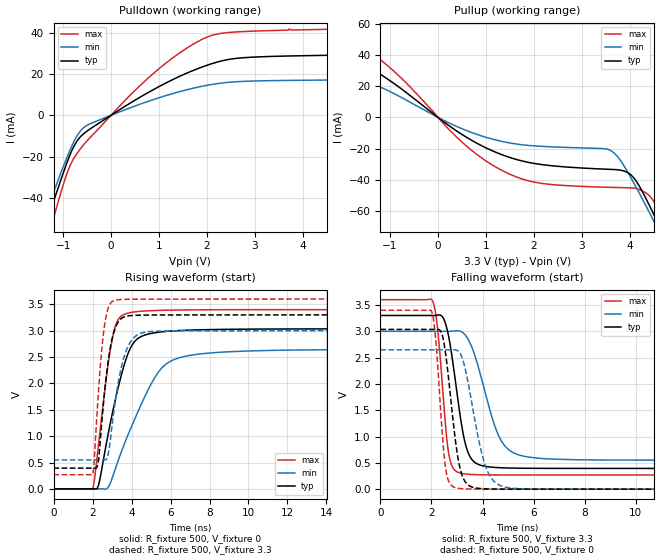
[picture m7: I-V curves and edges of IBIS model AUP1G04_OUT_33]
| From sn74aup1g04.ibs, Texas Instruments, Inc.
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[Model]   AUP1G04_OUT_33
Model_type  Output
Vref =   0
Rref =   1E6
Cref =   30p
Vmeas =   1.65
| variable   typ   min   max
C_comp   2.81pF   1.90pF   4.21pF
| C_pullup   3.21pF   1.90pF   4.21pF
| C_pulldown   2.42pF   2.21pF   2.99pF
[Temperature Range]   40   100   -40
| Ambient temperature   25   85   -40
[Voltage range]   3.3   3   3.6
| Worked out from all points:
|   slope of the pulldown table from 0 to 0.495 V, typ, clamps not added: 68.4 ohm
|   slope of the pullup table from 0 to 0.495 V, typ, clamps not added: 45.8 ohm
|   rising waveform, R_fixture 500, V_fixture 0: 20-80 % time 1.1ns typ, 1.9ns min, 694ps max; typ from 0 V to 3.04 V
|   falling waveform, R_fixture 500, V_fixture 3.3: 20-80 % time 533ps typ, 890ps min, 340ps max; typ from 3.3 V to 0.394 V
|   rising waveform, R_fixture 500, V_fixture 3.3: 20-80 % time 521ps typ, 675ps min, 407ps max; typ from 0.394 V to 3.3 V
|   falling waveform, R_fixture 500, V_fixture 0: 20-80 % time 440ps typ, 658ps min, 299ps max; typ from 3.04 V to 0 V
[Pulldown]
| AUP1G04_OUT_33
|   Voltage   I(typ)   I(min)   I(max)
-3.6V     -218.7mA   -196.3mA   -248.6mA
-1.515V   -64.37mA   -57.31mA   -75.82mA
-1.39V    -55.35mA   -49.29mA   -65.41mA
-1.275V   -47.14mA   -42mA      -55.89mA
-870mV    -19.93mA   -17.62mA   -25.18mA
-720mV    -12.85mA   -10.38mA   -18.82mA
-545mV    -8.444mA   -5.509mA   -13.51mA
940mV     13.13mA    8.018mA    21.36mA
1.5V      19.56mA    11.86mA    31.27mA
2.045V    24.53mA    14.67mA    38.2mA
3.1V      28.27mA    16.63mA    40.81mA
7.2V      29.73mA    17.36mA    42.67mA
[Pullup]
| AUP1G04_OUT_33
|   Voltage   I(typ)   I(min)   I(max)
-3.6V     42.88mA    27.27mA    57.92mA
-2.465V   31.53mA    19.52mA    45.85mA
-1.53V    32.87mA    22.09mA    44.95mA
-755mV    18.1mA     12.64mA    24.89mA
555mV     -11.98mA   -7.942mA   -17.3mA
1.65V     -27.07mA   -17.13mA   -38.31mA
3.61V     -33.32mA   -21.39mA   -44.82mA
4.08V     -38.63mA   -41.77mA   -45.28mA
4.375V    -54.25mA   -58.9mA    -49.24mA
4.565V    -66.24mA   -70.37mA   -57.33mA
4.775V    -80.02mA   -83.29mA   -71.37mA
7.2V      -250.7mA   -240.9mA   -257mA
[Ramp]
| AUP1G04_OUT_33
| variable   typ   min   max
dV/dt_r   1.82/1.11E-09   1.59/1.90E-09   2.04/6.96E-10
dV/dt_f   1.75/5.39E-10   1.48/8.97E-10   2.01/3.44E-10
R_load = 500
[Rising Waveform]
| AUP1G04_OUT_33
R_fixture =   500
C_fixture =   0
L_fixture =   0
V_fixture =   0
V_fixture_min = 0
V_fixture_max = 0
|   Time   V(typ)   V(min)   V(max)
0s        24.73nV    82.54nV    2.123nV
2.015ns   394.7uV    -31.45uV   11.77mV
2.325ns   95.32mV    471.5uV    901.5mV
3.01ns    1.421V     205.8mV    2.839V
3.29ns    1.883V     509.4mV    3.193V
3.755ns   2.499V     965.6mV    3.327V
4.305ns   2.846V     1.444V     3.363V
5.415ns   2.973V     2.233V     3.385V
7.01ns    3.012V     2.533V     3.395V
30.7ns    3.035V     2.647V     3.399V
[Falling Waveform]
| AUP1G04_OUT_33
R_fixture =   500
C_fixture =   0
L_fixture =   0
V_fixture =   3.3
V_fixture_min = 3
V_fixture_max = 3.6
|   Time   V(typ)   V(min)   V(max)
0s        3.3V       3V         3.6V
2.045ns   3.299V     3V         3.575V
2.24ns    3.307V     3V         3.046V
2.67ns    2.906V     2.999V     687.9mV
2.85ns    2.358V     3.004V     396.2mV
3.175ns   1.231V     2.991V     300.1mV
3.605ns   550mV      2.667V     278.4mV
4.675ns   407.6mV    970.1mV    270.2mV
5.7ns     397.1mV    617.9mV    269.4mV
30.7ns    394.1mV    550mV      269.3mV
[Rising Waveform]
| AUP1G04_OUT_33
R_fixture =   500
C_fixture =   0
L_fixture =   0
V_fixture =   3.3
V_fixture_min = 3
V_fixture_max = 3.6
|   Time   V(typ)   V(min)   V(max)
0s        394.1mV    550mV      269.3mV
2.01ns    394.4mV    550mV      285mV
2.285ns   495mV      550.3mV    1.735V
2.565ns   1.636V     550.3mV    2.96V
2.805ns   2.429V     661.7mV    3.429V
3.115ns   2.995V     1.524V     3.575V
3.43ns    3.216V     2.227V     3.591V
3.77ns    3.277V     2.659V     3.595V
4.77ns    3.296V     2.977V     3.598V
30.7ns    3.3V       3V         3.6V
[Falling Waveform]
| AUP1G04_OUT_33
R_fixture =   500
C_fixture =   0
L_fixture =   0
V_fixture =   0
V_fixture_min = 0
V_fixture_max = 0
|   Time   V(typ)   V(min)   V(max)
0s        3.035V     2.647V     3.399V
2.02ns    3.035V     2.647V     3.358V
2.17ns    3.036V     2.647V     2.814V
2.4ns     2.96V      2.647V     1.2V
2.545ns   2.6V       2.647V     420.6mV
2.985ns   755.6mV    2.639V     22.12mV
3.325ns   137mV      2.275V     6.183mV
4.12ns    6.52mV     430.1mV    545.1uV
4.925ns   841.3uV    34.25mV    75.7uV
30.7ns    -28.28nV   44.3nV     -28.36nV
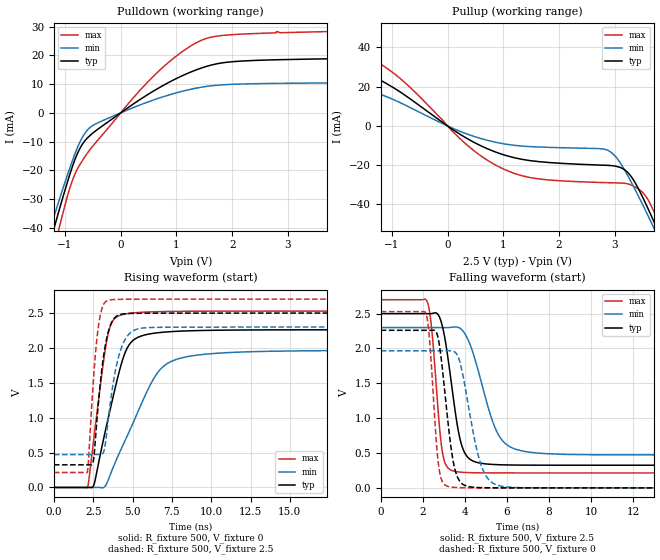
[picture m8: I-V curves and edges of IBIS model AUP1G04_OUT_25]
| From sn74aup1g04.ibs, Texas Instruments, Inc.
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[Model]   AUP1G04_OUT_25
Model_type  Output
Vref =   0
Rref =   1E6
Cref =   30p
Vmeas =   1.25
| variable   typ   min   max
C_comp   2.86pF   1.96pF   4.23pF
| C_pullup   3.21pF   1.96pF   4.23pF
| C_pulldown   2.51pF   2.22pF   3.08pF
[Temperature Range]   40   100   -40
| Ambient temperature   25   85   -40
[Voltage range]   2.5   2.3   2.7
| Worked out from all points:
|   slope of the pulldown table from 0 to 0.375 V, typ, clamps not added: 75.2 ohm
|   slope of the pullup table from 0 to 0.375 V, typ, clamps not added: 55.1 ohm
|   rising waveform, R_fixture 500, V_fixture 0: 20-80 % time 1.4ns typ, 2.41ns min, 863ps max; typ from 0 V to 2.26 V
|   falling waveform, R_fixture 500, V_fixture 2.5: 20-80 % time 632ps typ, 1.08ns min, 398ps max; typ from 2.5 V to 0.325 V
|   rising waveform, R_fixture 500, V_fixture 2.5: 20-80 % time 629ps typ, 806ps min, 486ps max; typ from 0.325 V to 2.5 V
|   falling waveform, R_fixture 500, V_fixture 0: 20-80 % time 511ps typ, 767ps min, 338ps max; typ from 2.26 V to 0 V
[Pulldown]
| AUP1G04_OUT_25
|   Voltage   I(typ)   I(min)   I(max)
-3.6V     -214mA     -193.5mA   -239.7mA
-1.26V    -44.55mA   -39.92mA   -52.42mA
-1.205V   -40.74mA   -36.52mA   -48.02mA
-1.115V   -34.57mA   -31.02mA   -40.91mA
-800mV    -15.22mA   -13.22mA   -20.4mA
-685mV    -10.84mA   -8.445mA   -16.54mA
-540mV    -7.689mA   -4.911mA   -12.5mA
675mV     8.558mA    5.038mA    14.35mA
1.105V    12.9mA     7.5mA      21.28mA
1.52V     16.03mA    9.129mA    25.76mA
2.585V    18.34mA    10.19mA    27.69mA
7.2V      19.61mA    10.73mA    29.61mA
[Pullup]
| AUP1G04_OUT_25
|   Voltage   I(typ)   I(min)   I(max)
-3.6V     37.28mA    23.5mA     50.35mA
-2.355V   24.65mA    15.21mA    35.57mA
-1.425V   26.01mA    17.2mA     35.58mA
-760mV    15.58mA    10.63mA    21.96mA
405mV     -7.279mA   -4.651mA   -11.04mA
1.05V     -15.07mA   -9.293mA   -22.54mA
2.845V    -20.04mA   -12.07mA   -28.88mA
3.17V     -22.17mA   -22.09mA   -29.2mA
3.455V    -33.67mA   -37.48mA   -32.73mA
3.685V    -47.61mA   -50.92mA   -42.5mA
3.82V     -56.28mA   -59.04mA   -51.47mA
7.2V      -294.7mA   -278.7mA   -311.5mA
[Ramp]
| AUP1G04_OUT_25
| variable   typ   min   max
dV/dt_r   1.36/1.41E-09   1.18/2.42E-09   1.52/8.64E-10
dV/dt_f   1.31/6.40E-10   1.10/1.09E-09   1.50/4.00E-10
R_load = 500
[Rising Waveform]
| AUP1G04_OUT_25
R_fixture =   500
C_fixture =   0
L_fixture =   0
V_fixture =   0
V_fixture_min = 0
V_fixture_max = 0
|   Time   V(typ)   V(min)   V(max)
0s        19.04nV    76.96nV    1.464nV
2.145ns   111.6uV    -21.3uV    7.06mV
2.56ns    45.93mV    151.5uV    734.1mV
3.39ns    927.9mV    71.34mV    2.134V
3.72ns    1.254V     258.6mV    2.378V
4.24ns    1.731V     532.4mV    2.47V
4.985ns   2.099V     900.1mV    2.501V
6.51ns    2.216V     1.619V     2.52V
8.265ns   2.243V     1.866V     2.525V
32.79ns   2.261V     1.966V     2.528V
[Falling Waveform]
| AUP1G04_OUT_25
R_fixture =   500
C_fixture =   0
L_fixture =   0
V_fixture =   2.5
V_fixture_min = 2.3
V_fixture_max = 2.7
|   Time   V(typ)   V(min)   V(max)
0s        2.5V       2.3V       2.7V
2.21ns    2.499V     2.3V       2.674V
2.42ns    2.501V     2.3V       2.293V
2.92ns    2.333V     2.299V     539.6mV
3.495ns   1.197V     2.309V     239.1mV
3.815ns   648.4mV    2.28V      224.9mV
4.195ns   422mV      2.097V     218.7mV
5.51ns    333.2mV    813.3mV    214.7mV
6.71ns    326.5mV    530.8mV    214.4mV
32.79ns   324.7mV    472mV      214.4mV
[Rising Waveform]
| AUP1G04_OUT_25
R_fixture =   500
C_fixture =   0
L_fixture =   0
V_fixture =   2.5
V_fixture_min = 2.3
V_fixture_max = 2.7
|   Time   V(typ)   V(min)   V(max)
0s        324.7mV    472mV      214.4mV
2.135ns   324.8mV    472mV      226.1mV
2.515ns   385.6mV    472.1mV    1.538V
2.775ns   1.062V     472.8mV    2.208V
3.165ns   1.887V     508.6mV    2.625V
3.42ns    2.195V     900.3mV    2.68V
3.82ns    2.42V      1.561V     2.694V
4.235ns   2.481V     1.964V     2.697V
5.43ns    2.497V     2.278V     2.699V
32.79ns   2.5V       2.3V       2.7V
[Falling Waveform]
| AUP1G04_OUT_25
R_fixture =   500
C_fixture =   0
L_fixture =   0
V_fixture =   0
V_fixture_min = 0
V_fixture_max = 0
|   Time   V(typ)   V(min)   V(max)
0s        2.261V     1.966V     2.528V
2.145ns   2.26V      1.966V     2.502V
2.325ns   2.261V     1.966V     2.114V
2.75ns    2.12V      1.966V     327.1mV
3.225ns   870.4mV    1.968V     18.26mV
3.49ns    314.8mV    1.954V     7.066mV
3.8ns     78.92mV    1.765V     2.637mV
4.755ns   3.373mV    342.4mV    175.7uV
5.695ns   401.2uV    25.75mV    23.75uV
32.79ns   -61.51nV   2.009nV    -16.98nV
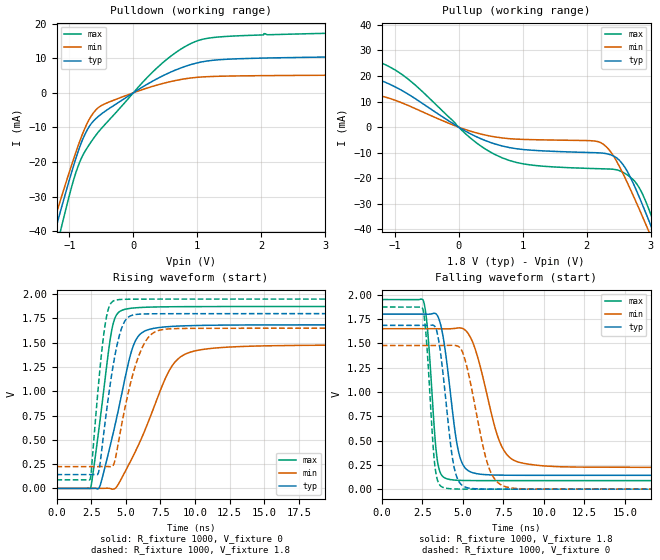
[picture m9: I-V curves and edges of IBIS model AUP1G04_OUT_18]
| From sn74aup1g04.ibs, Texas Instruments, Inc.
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[Model]   AUP1G04_OUT_18
Model_type  Output
Vref =   0
Rref =   1E6
Cref =   30p
Vmeas =   0.9
| variable   typ   min   max
C_comp   2.88pF   2.03pF   4.17pF
| C_pullup   3.17pF   2.03pF   4.17pF
| C_pulldown   2.60pF   2.23pF   3.12pF
[Temperature Range]   40   100   -40
| Ambient temperature   25   85   -40
[Voltage range]   1.8   1.65   1.95
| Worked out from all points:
|   slope of the pulldown table from 0 to 0.27 V, typ, clamps not added: 88.6 ohm
|   slope of the pullup table from 0 to 0.27 V, typ, clamps not added: 73.6 ohm
|   rising waveform, R_fixture 1000, V_fixture 0: 20-80 % time 1.58ns typ, 2.62ns min, 994ps max; typ from 0 V to 1.68 V
|   falling waveform, R_fixture 1000, V_fixture 1.8: 20-80 % time 754ps typ, 1.32ns min, 462ps max; typ from 1.8 V to 0.142 V
|   rising waveform, R_fixture 1000, V_fixture 1.8: 20-80 % time 1.03ns typ, 1.43ns min, 733ps max; typ from 0.142 V to 1.8 V
|   falling waveform, R_fixture 1000, V_fixture 0: 20-80 % time 678ps typ, 1.11ns min, 427ps max; typ from 1.68 V to 0 V
[Pulldown]
| AUP1G04_OUT_18
|   Voltage   I(typ)   I(min)   I(max)
-3.6V     -208.6mA   -189.9mA   -231.7mA
-1.27V    -43.16mA   -39.01mA   -50.14mA
-1.215V   -39.42mA   -35.66mA   -45.88mA
-1.125V   -33.38mA   -30.25mA   -38.97mA
-850mV    -16.31mA   -14.68mA   -20.63mA
-710mV    -10.41mA   -8.408mA   -15.6mA
-555mV    -6.973mA   -4.411mA   -11.55mA
360mV     3.96mA     2.185mA    7.039mA
705mV     6.927mA    3.722mA    12.18mA
1.03V     8.784mA    4.527mA    15.22mA
2.04V     10.05mA    4.966mA    17.1mA
7.2V      11.18mA    5.355mA    18.77mA
[Pullup]
| AUP1G04_OUT_18
|   Voltage   I(typ)   I(min)   I(max)
-3.6V     32.09mA    19.71mA    43.84mA
-3.16V    27.19mA    16.62mA    37.96mA
-2.12V    17.93mA    10.78mA    26.5mA
-1.525V   19.29mA    11.78mA    27.75mA
-1.155V   17.65mA    11.82mA    24.55mA
680mV     -7.373mA   -4.228mA   -12mA
2.185V    -10.05mA   -5.721mA   -16.26mA
2.485V    -12.35mA   -14.1mA    -16.81mA
2.725V    -21.81mA   -26.61mA   -20.47mA
2.94V     -34.55mA   -38.91mA   -30.08mA
3.085V    -43.74mA   -47.5mA    -39.77mA
7.2V      -334.8mA   -315.6mA   -357.6mA
[Ramp]
| AUP1G04_OUT_18
| variable   typ   min   max
dV/dt_r   1.01/1.59E-09   0.89/2.64E-09   1.13/9.97E-10
dV/dt_f   1.00/7.60E-10   0.86/1.33E-09   1.12/4.70E-10
R_load = 1000
[Rising Waveform]
| AUP1G04_OUT_18
R_fixture =   1000
C_fixture =   0
L_fixture =   0
V_fixture =   0
V_fixture_min = 0
V_fixture_max = 0
|   Time   V(typ)   V(min)   V(max)
0s        17.12nV    87.22nV    1.127nV
2.465ns   -5.406uV   -10.29uV   9.014mV
3.12ns    19.4mV     31.98uV    677.3mV
3.965ns   491.8mV    -5.256mV   1.612V
4.765ns   1.012V     122mV      1.837V
5.445ns   1.427V     308.6mV    1.857V
6.035ns   1.588V     483.7mV    1.863V
8.165ns   1.667V     1.22V      1.871V
9.705ns   1.676V     1.405V     1.872V
35.9ns    1.685V     1.477V     1.873V
[Falling Waveform]
| AUP1G04_OUT_18
R_fixture =   1000
C_fixture =   0
L_fixture =   0
V_fixture =   1.8
V_fixture_min = 1.65
V_fixture_max = 1.95
|   Time   V(typ)   V(min)   V(max)
0s        1.8V       1.65V      1.95V
2.57ns    1.8V       1.65V      1.934V
2.835ns   1.799V     1.65V      1.614V
3.405ns   1.791V     1.65V      321.5mV
4.025ns   1.283V     1.649V     106.2mV
4.605ns   496mV      1.655V     92.08mV
5.065ns   235mV      1.646V     89.38mV
7.3ns     144.2mV    476.5mV    87.92mV
8.495ns   142.7mV    275.2mV    87.9mV
35.9ns    142.2mV    224.7mV    87.89mV
[Rising Waveform]
| AUP1G04_OUT_18
R_fixture =   1000
C_fixture =   0
L_fixture =   0
V_fixture =   1.8
V_fixture_min = 1.65
V_fixture_max = 1.95
|   Time   V(typ)   V(min)   V(max)
0s        142.2mV    224.7mV    87.89mV
2.435ns   142.2mV    224.7mV    96.39mV
3.04ns    168.4mV    224.7mV    1.083V
3.44ns    602.9mV    225.3mV    1.617V
3.765ns   959.9mV    224.7mV    1.857V
4.2ns     1.354V     277.4mV    1.936V
4.865ns   1.705V     774.9mV    1.947V
5.785ns   1.792V     1.303V     1.949V
7.375ns   1.799V     1.627V     1.95V
35.9ns    1.8V       1.65V      1.95V
[Falling Waveform]
| AUP1G04_OUT_18
R_fixture =   1000
C_fixture =   0
L_fixture =   0
V_fixture =   0
V_fixture_min = 0
V_fixture_max = 0
|   Time   V(typ)   V(min)   V(max)
0s        1.685V     1.478V     1.873V
2.53ns    1.684V     1.478V     1.852V
2.75ns    1.684V     1.477V     1.541V
3.275ns   1.673V     1.477V     240.1mV
3.83ns    1.106V     1.478V     14.84mV
4.34ns    340mV      1.48V      3.122mV
4.74ns    82.91mV    1.466V     952.2uV
6.565ns   656.3uV    241.3mV    13.23uV
7.69ns    91.69uV    22.14mV    1.928uV
35.9ns    -45.54nV   13.76nV    -19.6nV
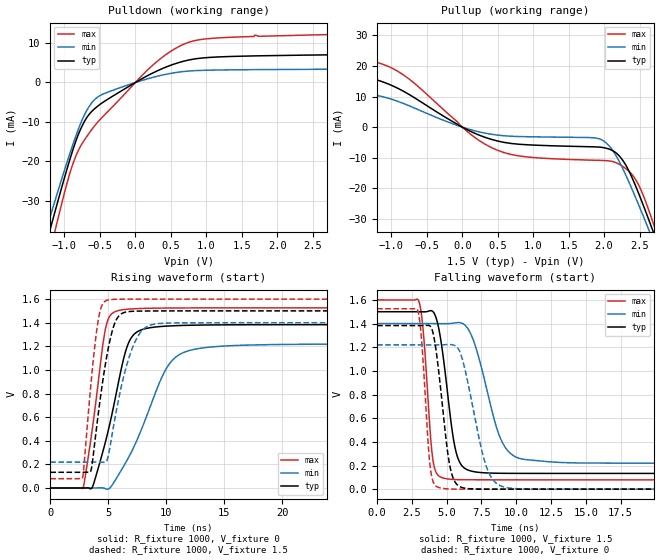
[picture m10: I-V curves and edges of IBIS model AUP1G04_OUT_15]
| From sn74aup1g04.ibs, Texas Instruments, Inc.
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[Model]   AUP1G04_OUT_15
Model_type  Output
Vref =   0
Rref =   1E6
Cref =   30p
Vmeas =   0.75
| variable   typ   min   max
C_comp   2.88pF   2.08pF   4.08pF
| C_pullup   3.12pF   2.08pF   4.08pF
| C_pulldown   2.65pF   2.24pF   3.14pF
[Temperature Range]   40   100   -40
| Ambient temperature   25   85   -40
[Voltage range]   1.5   1.4   1.6
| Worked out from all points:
|   slope of the pulldown table from 0 to 0.225 V, typ, clamps not added: 101 ohm
|   slope of the pullup table from 0 to 0.225 V, typ, clamps not added: 90.4 ohm
|   rising waveform, R_fixture 1000, V_fixture 0: 20-80 % time 1.91ns typ, 3.14ns min, 1.21ns max; typ from 0 V to 1.38 V
|   falling waveform, R_fixture 1000, V_fixture 1.5: 20-80 % time 891ps typ, 1.6ns min, 540ps max; typ from 1.5 V to 0.133 V
|   rising waveform, R_fixture 1000, V_fixture 1.5: 20-80 % time 1.23ns typ, 1.66ns min, 883ps max; typ from 0.133 V to 1.5 V
|   falling waveform, R_fixture 1000, V_fixture 0: 20-80 % time 802ps typ, 1.32ns min, 500ps max; typ from 1.38 V to 0 V
[Pulldown]
| AUP1G04_OUT_15
|   Voltage   I(typ)   I(min)   I(max)
-3.6V     -206.1mA   -188.4mA   -227.8mA
-1.265V   -41.59mA   -37.94mA   -47.65mA
-1.21V    -37.9mA    -34.62mA   -43.48mA
-1.11V    -31.29mA   -28.67mA   -36mA
-945mV    -20.84mA   -19.21mA   -24.37mA
-855mV    -15.7mA    -14.39mA   -19.43mA
-720mV    -9.972mA   -8.297mA   -14.65mA
-570mV    -6.595mA   -4.269mA   -10.91mA
260mV     2.544mA    1.373mA    4.642mA
810mV     5.906mA    2.979mA    10.53mA
1.685V    6.762mA    3.268mA    12.01mA
7.2V      7.827mA    3.609mA    13.77mA
[Pullup]
| AUP1G04_OUT_15
|   Voltage   I(typ)   I(min)   I(max)
-3.6V     29.66mA    17.95mA    40.7mA
-2.925V   22.54mA    13.64mA    31.9mA
-2.13V    15.77mA    9.503mA    23.16mA
-1.025V   13.91mA    9.322mA    19.64mA
130mV     -1.525mA   -910.1uA   -2.565mA
590mV     -4.979mA   -2.819mA   -8.32mA
1.925V    -6.506mA   -3.765mA   -10.85mA
2.175V    -8.513mA   -9.57mA    -11.67mA
2.395V    -16.55mA   -20.31mA   -15.49mA
2.615V    -29.32mA   -32.63mA   -26.15mA
2.72V     -35.89mA   -38.74mA   -33.2mA
7.2V      -352.6mA   -330.3mA   -379.5mA
[Ramp]
| AUP1G04_OUT_15
| variable   typ   min   max
dV/dt_r   0.83/1.92E-09   0.74/3.17E-09   0.92/1.21E-09
dV/dt_f   0.83/9.00E-10   0.71/1.61E-09   0.92/5.47E-10
R_load = 1000
[Rising Waveform]
| AUP1G04_OUT_15
R_fixture =   1000
C_fixture =   0
L_fixture =   0
V_fixture =   0
V_fixture_min = 0
V_fixture_max = 0
|   Time   V(typ)   V(min)   V(max)
0s        16.57nV    92.2nV     986.7pV
2.83ns    10.8uV     -14.34uV   2.597mV
3.62ns    5.798mV    14.15uV    498.4mV
4.695ns   368.1mV    -3.544mV   1.316V
5.58ns    750mV      63.2mV     1.493V
6.465ns   1.148V     208.9mV    1.512V
7.18ns    1.297V     343.1mV    1.518V
9.865ns   1.37V      987.6mV    1.524V
11.55ns   1.377V     1.15V      1.525V
34.99ns   1.383V     1.22V      1.525V
[Falling Waveform]
| AUP1G04_OUT_15
R_fixture =   1000
C_fixture =   0
L_fixture =   0
V_fixture =   1.5
V_fixture_min = 1.4
V_fixture_max = 1.6
|   Time   V(typ)   V(min)   V(max)
0s        1.5V       1.4V       1.6V
3.005ns   1.5V       1.4V       1.586V
3.325ns   1.499V     1.4V       1.321V
3.985ns   1.504V     1.4V       269.8mV
4.675ns   1.184V     1.399V     97.16mV
5.635ns   333.7mV    1.406V     81.1mV
6.685ns   155.5mV    1.324V     79.35mV
8.785ns   134.4mV    453.5mV    79.09mV
10.17ns   133.4mV    262.5mV    79.08mV
34.99ns   133.1mV    219.3mV    79.08mV
[Rising Waveform]
| AUP1G04_OUT_15
R_fixture =   1000
C_fixture =   0
L_fixture =   0
V_fixture =   1.5
V_fixture_min = 1.4
V_fixture_max = 1.6
|   Time   V(typ)   V(min)   V(max)
0s        133.1mV    219.3mV    79.08mV
2.77ns    133.2mV    219.3mV    82.36mV
3.495ns   144.9mV    219.4mV    869.6mV
3.99ns    512.1mV    219.8mV    1.325V
4.36ns    793.1mV    219.3mV    1.521V
4.82ns    1.088V     224.4mV    1.587V
5.64ns    1.414V     625.5mV    1.598V
6.75ns    1.494V     1.094V     1.599V
8.53ns    1.499V     1.376V     1.6V
34.99ns   1.5V       1.4V       1.6V
[Falling Waveform]
| AUP1G04_OUT_15
R_fixture =   1000
C_fixture =   0
L_fixture =   0
V_fixture =   0
V_fixture_min = 0
V_fixture_max = 0
|   Time   V(typ)   V(min)   V(max)
0s        1.383V     1.22V      1.525V
2.94ns    1.383V     1.22V      1.505V
3.205ns   1.383V     1.22V      1.243V
3.805ns   1.379V     1.219V     197.7mV
4.405ns   1.017V     1.22V      15.11mV
5.095ns   291mV      1.222V     2.292mV
5.565ns   68.07mV    1.216V     623.7uV
7.83ns    351.1uV    197.9mV    4.746uV
9.02ns    55.72uV    21.54mV    787.5nV
34.99ns   -46.99nV   11.25nV    -50.87nV
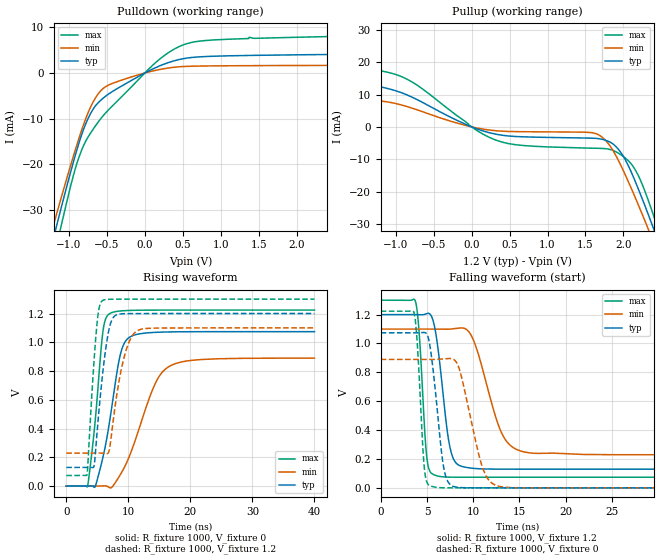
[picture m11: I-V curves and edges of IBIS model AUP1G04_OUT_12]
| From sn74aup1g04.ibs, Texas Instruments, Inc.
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[Model]   AUP1G04_OUT_12
Model_type  Output
Vref =   0
Rref =   1E6
Cref =   30p
Vmeas =   0.6
| variable   typ   min   max
C_comp   2.85pF   2.12pF   3.93pF
| C_pullup   3.03pF   2.12pF   3.93pF
| C_pulldown   2.67pF   2.23pF   3.17pF
[Temperature Range]   40   100   -40
| Ambient temperature   25   85   -40
[Voltage range]   1.2   1.1   1.3
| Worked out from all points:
|   slope of the pulldown table from 0 to 0.18 V, typ, clamps not added: 125 ohm
|   slope of the pullup table from 0 to 0.18 V, typ, clamps not added: 123 ohm
|   rising waveform, R_fixture 1000, V_fixture 0: 20-80 % time 2.46ns typ, 4.44ns min, 1.51ns max; typ from 0 V to 1.07 V
|   falling waveform, R_fixture 1000, V_fixture 1.2: 20-80 % time 1.16ns typ, 2.36ns min, 659ps max; typ from 1.2 V to 0.129 V
|   rising waveform, R_fixture 1000, V_fixture 1.2: 20-80 % time 1.56ns typ, 2.1ns min, 1.1ns max; typ from 0.129 V to 1.2 V
|   falling waveform, R_fixture 1000, V_fixture 0: 20-80 % time 1.05ns typ, 1.88ns min, 614ps max; typ from 1.07 V to 0 V
[Pulldown]
| AUP1G04_OUT_12
|   Voltage   I(typ)   I(min)   I(max)
-3.6V     -203.6mA   -186.6mA   -224.6mA
-1.215V   -36.77mA   -33.88mA   -41.55mA
-1.165V   -33.49mA   -30.92mA   -37.89mA
-1.12V    -30.57mA   -28.28mA   -34.63mA
-1.08V    -28mA      -25.95mA   -31.76mA
-930mV    -18.76mA   -17.53mA   -21.68mA
-820mV    -12.87mA   -11.86mA   -16.33mA
-695mV    -8.261mA   -6.747mA   -12.62mA
-580mV    -5.938mA   -3.862mA   -9.962mA
160mV     1.298mA    643.5uA    2.533mA
610mV     3.376mA    1.481mA    6.659mA
7.2V      4.761mA    1.852mA    9.574mA
[Pullup]
| AUP1G04_OUT_12
|   Voltage   I(typ)   I(min)   I(max)
-3.6V     26.64mA    8.226mA    37.8mA
-3.065V   21.41mA    10.49mA    30.92mA
-2.05V    13.06mA    7.529mA    19.66mA
-955mV    10.79mA    6.951mA    15.81mA
400mV     -2.561mA   -1.314mA   -4.679mA
1.61V     -3.491mA   -1.891mA   -6.566mA
1.87V     -5.387mA   -7.563mA   -7.321mA
2.095V    -13.49mA   -18.49mA   -11.17mA
2.33V     -27.16mA   -31.66mA   -22.8mA
2.44V     -34.07mA   -38.08mA   -30.25mA
2.51V     -38.55mA   -42.22mA   -35.17mA
7.2V      -371mA     -348.5mA   -398.6mA
[Ramp]
| AUP1G04_OUT_12
| variable   typ   min   max
dV/dt_r   0.65/2.49E-09   0.54/4.52E-09   0.74/1.52E-09
dV/dt_f   0.65/1.17E-09   0.53/2.38E-09   0.74/6.65E-10
R_load = 1000
[Rising Waveform]
| AUP1G04_OUT_12
R_fixture =   1000
C_fixture =   0
L_fixture =   0
V_fixture =   0
V_fixture_min = 0
V_fixture_max = 0
|   Time   V(typ)   V(min)   V(max)
0s        17.04nV    106.6nV    899pV
3.44ns    -21.19uV   -6.531uV   -1.218mV
4.645ns   -4.917mV   -30.76uV   443.9mV
5.875ns   193mV      902uV      1.061V
6.93ns    433.3mV    -9.627mV   1.197V
8.475ns   865.8mV    62.39mV    1.216V
9.5ns     1.004V     141.5mV    1.22V
14.13ns   1.069V     692.6mV    1.224V
16.48ns   1.072V     829mV      1.224V
40ns      1.074V     889.8mV    1.224V
[Falling Waveform]
| AUP1G04_OUT_12
R_fixture =   1000
C_fixture =   0
L_fixture =   0
V_fixture =   1.2
V_fixture_min = 1.1
V_fixture_max = 1.3
|   Time   V(typ)   V(min)   V(max)
0s        1.2V       1.1V       1.3V
3.755ns   1.2V       1.1V       1.292V
4.165ns   1.199V     1.1V       1.068V
4.96ns    1.206V     1.1V       226.9mV
5.7ns     1.15V      1.1V       92.62mV
7.395ns   311.1mV    1.099V     74.28mV
8.515ns   154.5mV    1.107V     73.65mV
9.91ns    135.8mV    1.04V      73.55mV
14.76ns   129.5mV    263.8mV    73.54mV
40ns      129.5mV    229.3mV    73.54mV
[Rising Waveform]
| AUP1G04_OUT_12
R_fixture =   1000
C_fixture =   0
L_fixture =   0
V_fixture =   1.2
V_fixture_min = 1.1
V_fixture_max = 1.3
|   Time   V(typ)   V(min)   V(max)
0s        129.5mV    229.3mV    73.54mV
3.355ns   129.5mV    229.3mV    77.83mV
4.5ns     144.1mV    229.4mV    882.7mV
5.155ns   466.6mV    229.6mV    1.201V
5.845ns   772.9mV    228.9mV    1.29V
6.855ns   1.081V     238.4mV    1.299V
7.45ns    1.163V     414.1mV    1.299V
9.3ns     1.198V     891mV      1.3V
11.44ns   1.2V       1.08V      1.3V
40ns      1.2V       1.1V       1.3V
[Falling Waveform]
| AUP1G04_OUT_12
R_fixture =   1000
C_fixture =   0
L_fixture =   0
V_fixture =   0
V_fixture_min = 0
V_fixture_max = 0
|   Time   V(typ)   V(min)   V(max)
0s        1.074V     889.8mV    1.224V
3.615ns   1.074V     889.8mV    1.211V
3.975ns   1.074V     889.7mV    978mV
4.695ns   1.076V     889.6mV    152.9mV
5.32ns    984.3mV    889.5mV    15.38mV
6.76ns    160.6mV    892.9mV    605.9uV
7.775ns   12.11mV    893.1mV    54.2uV
11ns      58.73uV    143.6mV    191.5nV
12.4ns    10.6uV     18.61mV    97.26nV
40ns      -48.57nV   98.07nV    -88.43nV
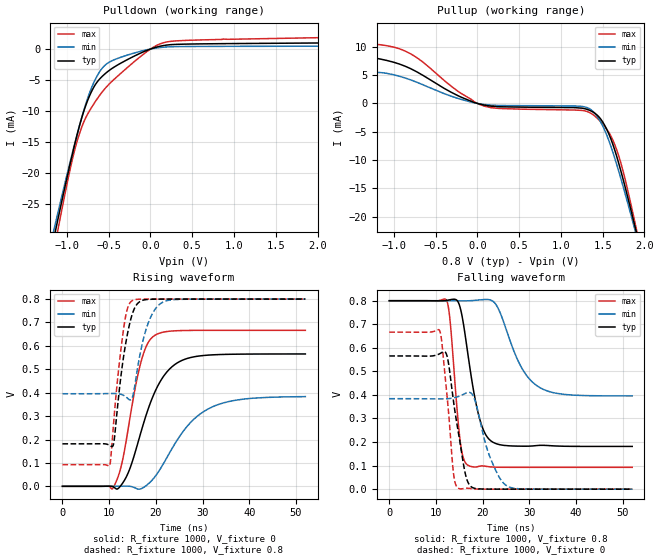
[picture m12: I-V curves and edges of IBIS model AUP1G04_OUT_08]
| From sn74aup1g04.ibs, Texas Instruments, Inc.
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[Model]   AUP1G04_OUT_08
Model_type  Output
Vref =   0
Rref =   1E6
Cref =   30p
Vmeas =   0.4
| variable   typ   min   max
C_comp   2.71pF   2.19pF   3.34pF
| C_pullup   2.77pF   2.20pF   3.34pF
| C_pulldown   2.64pF   2.19pF   3.08pF
[Temperature Range]   40   100   -40
| Ambient temperature   25   85   -40
[Voltage range]   0.8   0.8   0.8
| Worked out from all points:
|   slope of the pulldown table from 0 to 0.12 V, typ, clamps not added: 257 ohm
|   slope of the pullup table from 0 to 0.12 V, typ, clamps not added: 309 ohm
|   rising waveform, R_fixture 1000, V_fixture 0: 20-80 % time 5.99ns typ, 8.3ns min, 3.75ns max; typ from 0 V to 0.565 V
|   falling waveform, R_fixture 1000, V_fixture 0.8: 20-80 % time 3.18ns typ, 5.32ns min, 1.73ns max; typ from 0.8 V to 0.181 V
|   rising waveform, R_fixture 1000, V_fixture 0.8: 20-80 % time 2.56ns typ, 2.96ns min, 2.18ns max; typ from 0.181 V to 0.8 V
|   falling waveform, R_fixture 1000, V_fixture 0: 20-80 % time 2.58ns typ, 3.61ns min, 1.74ns max; typ from 0.566 V to 0 V
[Pulldown]
| AUP1G04_OUT_08
|   Voltage   I(typ)   I(min)   I(max)
-3.6V     -200.3mA   -184.7mA   -219.1mA
-1.155V   -30.43mA   -29.11mA   -32.45mA
-1.105V   -27.26mA   -26.22mA   -28.93mA
-940mV    -17.24mA   -17.01mA   -18.09mA
-865mV    -13.13mA   -13.1mA    -14.27mA
-745mV    -8.043mA   -7.657mA   -10.32mA
-630mV    -5.174mA   -4.128mA   -7.88mA
-470mV    -3.218mA   -1.946mA   -5.328mA
5mV       23.8uA     12.51uA    45.54uA
245mV     711.3uA    371.9uA    1.246mA
870mV     872.1uA    431.7uA    1.618mA
7.2V      1.459mA    578.6uA    3.138mA
[Pullup]
| AUP1G04_OUT_08
|   Voltage   I(typ)   I(min)   I(max)
-3.6V     2.784mA    339.2uA    9.474mA
-2.56V    3.921mA    663.8uA    11.14mA
-2.01V    6.261mA    1.269mA    13.37mA
-1.185V   7.906mA    5.477mA    10.41mA
-800mV    6.149mA    4.169mA    8.776mA
80mV      -287uA     -177.3uA   -461.9uA
1.285V    -921uA     -607uA     -1.305mA
1.455V    -2.355mA   -2.736mA   -2.902mA
1.625V    -7.333mA   -8.725mA   -6.56mA
1.74V     -13.09mA   -14.38mA   -11.68mA
1.905V    -22.78mA   -23.32mA   -22.23mA
7.2V      -396.8mA   -367.4mA   -431.7mA
[Ramp]
| AUP1G04_OUT_08
| variable   typ   min   max
dV/dt_r   0.35/6.07E-09   0.24/8.45E-09   0.41/3.81E-09
dV/dt_f   0.37/3.20E-09   0.25/5.35E-09   0.43/1.75E-09
R_load = 1000
[Rising Waveform]
| AUP1G04_OUT_08
R_fixture =   1000
C_fixture =   0
L_fixture =   0
V_fixture =   0
V_fixture_min = 0
V_fixture_max = 0
|   Time   V(typ)   V(min)   V(max)
0s        23.71nV    153.5nV    1.008nV
10.84ns   -1.553mV   8.404uV    -7.179mV
12.37ns   -257.6uV   384.2uV    69.72mV
13.66ns   39.65mV    764.4uV    195.8mV
16.86ns   234.5mV    -10.23mV   534mV
18.19ns   320.3mV    7.156mV    607.9mV
19.74ns   401mV      39.28mV    644.5mV
24.17ns   521.9mV    184.8mV    664.5mV
31.2ns    560.5mV    330.6mV    666.4mV
52ns      565.5mV    383.2mV    666.5mV
[Falling Waveform]
| AUP1G04_OUT_08
R_fixture =   1000
C_fixture =   0
L_fixture =   0
V_fixture =   0.8
V_fixture_min = 0.8
V_fixture_max = 0.8
|   Time   V(typ)   V(min)   V(max)
0s        800mV      800mV      800mV
12.29ns   801.4mV    799.9mV    800mV
13.05ns   804.3mV    799.8mV    706.7mV
15.18ns   769.6mV    799.5mV    202.3mV
16.78ns   579.5mV    799.6mV    102.1mV
19.34ns   298.1mV    803.5mV    97.67mV
22.14ns   199.8mV    798.4mV    93.84mV
28.05ns   182.6mV    525.2mV    92.73mV
31.69ns   185.3mV    437.9mV    92.72mV
52ns      181.5mV    395.7mV    92.72mV
[Rising Waveform]
| AUP1G04_OUT_08
R_fixture =   1000
C_fixture =   0
L_fixture =   0
V_fixture =   0.8
V_fixture_min = 0.8
V_fixture_max = 0.8
|   Time   V(typ)   V(min)   V(max)
0s        181.5mV    395.5mV    92.72mV
10.13ns   174.7mV    396.3mV    90.29mV
11.03ns   189.7mV    396.6mV    288mV
12.95ns   534.8mV    389.9mV    651.6mV
13.84ns   642.5mV    377.8mV    753.8mV
14.88ns   731.3mV    375.7mV    792.6mV
16.11ns   781.3mV    508.1mV    799mV
17.94ns   797.7mV    672.8mV    799.8mV
21.31ns   799.8mV    784.8mV    800mV
52ns      800mV      800mV      800mV
[Falling Waveform]
| AUP1G04_OUT_08
R_fixture =   1000
C_fixture =   0
L_fixture =   0
V_fixture =   0
V_fixture_min = 0
V_fixture_max = 0
|   Time   V(typ)   V(min)   V(max)
0s        565.5mV    384mV      666.5mV
10.8ns    575mV      383mV      671.7mV
12.43ns   560mV      383.8mV    382.9mV
13.74ns   372.8mV    387.7mV    67.48mV
14.73ns   247.2mV    393mV      4.364mV
16.21ns   70.49mV    405.8mV    3.82mV
17.26ns   15.42mV    410.3mV    3.037mV
21.61ns   182.5uV    132.9mV    18.63uV
25.31ns   12.07uV    12.47mV    814.4nV
52ns      103.3nV    1.28uV     1.206nV
